VERSION 5.8 ;
BUSBITCHARS "[]" ;
DIVIDERCHAR "/" ;

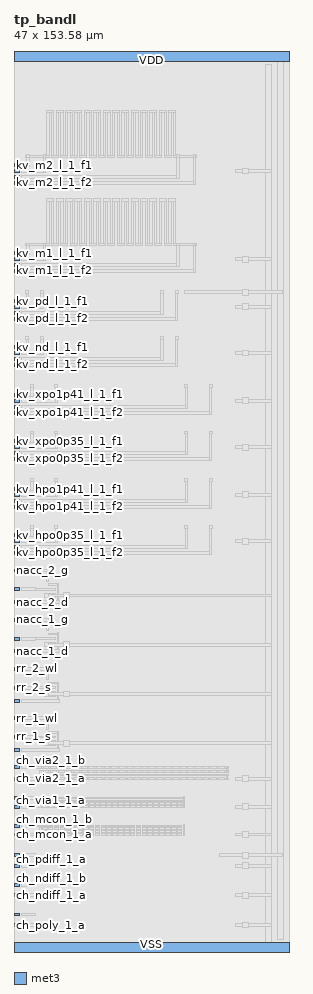
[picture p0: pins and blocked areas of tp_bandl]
MACRO tp_bandl
  CLASS BLOCK ;
  FOREIGN tp_bandl 0 0 ;
  ORIGIN 0 0 ;
  SIZE 47.000 BY 153.580 ;
  SYMMETRY X Y ;
  PIN VDD
    DIRECTION INOUT ;
    USE POWER ;
    PORT
      LAYER met3 ;
        RECT 0.000 151.980 47.000 153.580 ;
    END
  END VDD
  PIN VSS
    DIRECTION INOUT ;
    USE GROUND ;
    PORT
      LAYER met3 ;
        RECT 0.000 0.000 47.000 1.600 ;
    END
  END VSS
  PIN ch_mcon_1_a
    DIRECTION INOUT ;
    USE SIGNAL ;
    PORT
      LAYER met3 ;
        RECT 0.000 19.800 1.000 20.300 ;
    END
  END ch_mcon_1_a
  PIN ch_mcon_1_b
    DIRECTION INOUT ;
    USE SIGNAL ;
    PORT
      LAYER met3 ;
        RECT 0.000 21.300 1.000 21.800 ;
    END
  END ch_mcon_1_b
  PIN ch_ndiff_1_a
    DIRECTION INOUT ;
    USE SIGNAL ;
    PORT
      LAYER met3 ;
        RECT 0.000 9.400 1.000 9.900 ;
    END
  END ch_ndiff_1_a
  PIN ch_ndiff_1_b
    DIRECTION INOUT ;
    USE SIGNAL ;
    PORT
      LAYER met3 ;
        RECT 0.000 11.200 1.000 11.700 ;
    END
  END ch_ndiff_1_b
  PIN ch_pdiff_1_a
    DIRECTION INOUT ;
    USE SIGNAL ;
    PORT
      LAYER met3 ;
        RECT 0.000 14.450 1.000 14.950 ;
    END
  END ch_pdiff_1_a
  PIN ch_pdiff_1_b
    DIRECTION INOUT ;
    USE SIGNAL ;
    PORT
      LAYER met3 ;
        RECT 0.000 16.250 1.000 16.750 ;
    END
  END ch_pdiff_1_b
  PIN ch_poly_1_a
    DIRECTION INOUT ;
    USE SIGNAL ;
    PORT
      LAYER met3 ;
        RECT 0.000 4.350 1.000 4.850 ;
    END
  END ch_poly_1_a
  PIN ch_poly_1_b
    DIRECTION INOUT ;
    USE SIGNAL ;
    PORT
      LAYER met3 ;
        RECT 0.000 6.150 1.000 6.650 ;
    END
  END ch_poly_1_b
  PIN ch_via1_1_a
    DIRECTION INOUT ;
    USE SIGNAL ;
    PORT
      LAYER met3 ;
        RECT 0.000 24.550 1.000 25.050 ;
    END
  END ch_via1_1_a
  PIN ch_via1_1_b
    DIRECTION INOUT ;
    USE SIGNAL ;
    PORT
      LAYER met3 ;
        RECT 0.000 26.050 1.000 26.550 ;
    END
  END ch_via1_1_b
  PIN ch_via2_1_a
    DIRECTION INOUT ;
    USE SIGNAL ;
    PORT
      LAYER met3 ;
        RECT 0.000 29.300 1.000 29.800 ;
    END
  END ch_via2_1_a
  PIN ch_via2_1_b
    DIRECTION INOUT ;
    USE SIGNAL ;
    PORT
      LAYER met3 ;
        RECT 0.000 31.250 1.000 31.750 ;
    END
  END ch_via2_1_b
  PIN kv_hpo0p35_l_1_f1
    DIRECTION INOUT ;
    USE SIGNAL ;
    PORT
      LAYER met3 ;
        RECT 0.000 70.850 1.000 71.350 ;
    END
  END kv_hpo0p35_l_1_f1
  PIN kv_hpo0p35_l_1_f2
    DIRECTION INOUT ;
    USE SIGNAL ;
    PORT
      LAYER met3 ;
        RECT 0.000 67.850 1.000 68.350 ;
    END
  END kv_hpo0p35_l_1_f2
  PIN kv_hpo0p35_l_1_s1
    DIRECTION INOUT ;
    USE SIGNAL ;
    PORT
      LAYER met3 ;
        RECT 0.000 69.850 1.000 70.350 ;
    END
  END kv_hpo0p35_l_1_s1
  PIN kv_hpo0p35_l_1_s2
    DIRECTION INOUT ;
    USE SIGNAL ;
    PORT
      LAYER met3 ;
        RECT 0.000 68.850 1.000 69.350 ;
    END
  END kv_hpo0p35_l_1_s2
  PIN kv_hpo1p41_l_1_f1
    DIRECTION INOUT ;
    USE SIGNAL ;
    PORT
      LAYER met3 ;
        RECT 0.000 78.750 1.000 79.250 ;
    END
  END kv_hpo1p41_l_1_f1
  PIN kv_hpo1p41_l_1_f2
    DIRECTION INOUT ;
    USE SIGNAL ;
    PORT
      LAYER met3 ;
        RECT 0.000 75.750 1.000 76.250 ;
    END
  END kv_hpo1p41_l_1_f2
  PIN kv_hpo1p41_l_1_s1
    DIRECTION INOUT ;
    USE SIGNAL ;
    PORT
      LAYER met3 ;
        RECT 0.000 77.750 1.000 78.250 ;
    END
  END kv_hpo1p41_l_1_s1
  PIN kv_hpo1p41_l_1_s2
    DIRECTION INOUT ;
    USE SIGNAL ;
    PORT
      LAYER met3 ;
        RECT 0.000 76.750 1.000 77.250 ;
    END
  END kv_hpo1p41_l_1_s2
  PIN kv_m1_l_1_f1
    DIRECTION INOUT ;
    USE SIGNAL ;
    PORT
      LAYER met3 ;
        RECT 0.000 118.985 1.000 119.485 ;
    END
  END kv_m1_l_1_f1
  PIN kv_m1_l_1_f2
    DIRECTION INOUT ;
    USE SIGNAL ;
    PORT
      LAYER met3 ;
        RECT 0.000 115.985 1.000 116.485 ;
    END
  END kv_m1_l_1_f2
  PIN kv_m1_l_1_s1
    DIRECTION INOUT ;
    USE SIGNAL ;
    PORT
      LAYER met3 ;
        RECT 0.000 117.985 1.000 118.485 ;
    END
  END kv_m1_l_1_s1
  PIN kv_m1_l_1_s2
    DIRECTION INOUT ;
    USE SIGNAL ;
    PORT
      LAYER met3 ;
        RECT 0.000 116.985 1.000 117.485 ;
    END
  END kv_m1_l_1_s2
  PIN kv_m2_l_1_f1
    DIRECTION INOUT ;
    USE SIGNAL ;
    PORT
      LAYER met3 ;
        RECT 0.000 134.035 1.000 134.535 ;
    END
  END kv_m2_l_1_f1
  PIN kv_m2_l_1_f2
    DIRECTION INOUT ;
    USE SIGNAL ;
    PORT
      LAYER met3 ;
        RECT 0.000 131.035 1.000 131.535 ;
    END
  END kv_m2_l_1_f2
  PIN kv_m2_l_1_s1
    DIRECTION INOUT ;
    USE SIGNAL ;
    PORT
      LAYER met3 ;
        RECT 0.000 133.035 1.000 133.535 ;
    END
  END kv_m2_l_1_s1
  PIN kv_m2_l_1_s2
    DIRECTION INOUT ;
    USE SIGNAL ;
    PORT
      LAYER met3 ;
        RECT 0.000 132.035 1.000 132.535 ;
    END
  END kv_m2_l_1_s2
  PIN kv_nd_l_1_f1
    DIRECTION INOUT ;
    USE SIGNAL ;
    PORT
      LAYER met3 ;
        RECT 0.000 102.960 1.000 103.460 ;
    END
  END kv_nd_l_1_f1
  PIN kv_nd_l_1_f2
    DIRECTION INOUT ;
    USE SIGNAL ;
    PORT
      LAYER met3 ;
        RECT 0.000 99.960 1.000 100.460 ;
    END
  END kv_nd_l_1_f2
  PIN kv_nd_l_1_s1
    DIRECTION INOUT ;
    USE SIGNAL ;
    PORT
      LAYER met3 ;
        RECT 0.000 101.960 1.000 102.460 ;
    END
  END kv_nd_l_1_s1
  PIN kv_nd_l_1_s2
    DIRECTION INOUT ;
    USE SIGNAL ;
    PORT
      LAYER met3 ;
        RECT 0.000 100.960 1.000 101.460 ;
    END
  END kv_nd_l_1_s2
  PIN kv_pd_l_1_f1
    DIRECTION INOUT ;
    USE SIGNAL ;
    PORT
      LAYER met3 ;
        RECT 0.000 110.835 1.000 111.335 ;
    END
  END kv_pd_l_1_f1
  PIN kv_pd_l_1_f2
    DIRECTION INOUT ;
    USE SIGNAL ;
    PORT
      LAYER met3 ;
        RECT 0.000 107.835 1.000 108.335 ;
    END
  END kv_pd_l_1_f2
  PIN kv_pd_l_1_s1
    DIRECTION INOUT ;
    USE SIGNAL ;
    PORT
      LAYER met3 ;
        RECT 0.000 109.835 1.000 110.335 ;
    END
  END kv_pd_l_1_s1
  PIN kv_pd_l_1_s2
    DIRECTION INOUT ;
    USE SIGNAL ;
    PORT
      LAYER met3 ;
        RECT 0.000 108.835 1.000 109.335 ;
    END
  END kv_pd_l_1_s2
  PIN kv_xpo0p35_l_1_f1
    DIRECTION INOUT ;
    USE SIGNAL ;
    PORT
      LAYER met3 ;
        RECT 0.000 86.905 1.000 87.405 ;
    END
  END kv_xpo0p35_l_1_f1
  PIN kv_xpo0p35_l_1_f2
    DIRECTION INOUT ;
    USE SIGNAL ;
    PORT
      LAYER met3 ;
        RECT 0.000 83.905 1.000 84.405 ;
    END
  END kv_xpo0p35_l_1_f2
  PIN kv_xpo0p35_l_1_s1
    DIRECTION INOUT ;
    USE SIGNAL ;
    PORT
      LAYER met3 ;
        RECT 0.000 85.905 1.000 86.405 ;
    END
  END kv_xpo0p35_l_1_s1
  PIN kv_xpo0p35_l_1_s2
    DIRECTION INOUT ;
    USE SIGNAL ;
    PORT
      LAYER met3 ;
        RECT 0.000 84.905 1.000 85.405 ;
    END
  END kv_xpo0p35_l_1_s2
  PIN kv_xpo1p41_l_1_f1
    DIRECTION INOUT ;
    USE SIGNAL ;
    PORT
      LAYER met3 ;
        RECT 0.000 94.805 1.000 95.305 ;
    END
  END kv_xpo1p41_l_1_f1
  PIN kv_xpo1p41_l_1_f2
    DIRECTION INOUT ;
    USE SIGNAL ;
    PORT
      LAYER met3 ;
        RECT 0.000 91.805 1.000 92.305 ;
    END
  END kv_xpo1p41_l_1_f2
  PIN kv_xpo1p41_l_1_s1
    DIRECTION INOUT ;
    USE SIGNAL ;
    PORT
      LAYER met3 ;
        RECT 0.000 93.805 1.000 94.305 ;
    END
  END kv_xpo1p41_l_1_s1
  PIN kv_xpo1p41_l_1_s2
    DIRECTION INOUT ;
    USE SIGNAL ;
    PORT
      LAYER met3 ;
        RECT 0.000 92.805 1.000 93.305 ;
    END
  END kv_xpo1p41_l_1_s2
  PIN nacc_1_d
    DIRECTION INOUT ;
    USE SIGNAL ;
    PORT
      LAYER met3 ;
        RECT 0.000 51.050 1.000 51.550 ;
    END
  END nacc_1_d
  PIN nacc_1_g
    DIRECTION INOUT ;
    USE SIGNAL ;
    PORT
      LAYER met3 ;
        RECT 0.000 56.450 1.000 56.950 ;
    END
  END nacc_1_g
  PIN nacc_1_s
    DIRECTION INOUT ;
    USE SIGNAL ;
    PORT
      LAYER met3 ;
        RECT 0.000 53.240 1.000 53.740 ;
    END
  END nacc_1_s
  PIN nacc_2_d
    DIRECTION INOUT ;
    USE SIGNAL ;
    PORT
      LAYER met3 ;
        RECT 0.000 59.450 1.000 59.950 ;
    END
  END nacc_2_d
  PIN nacc_2_g
    DIRECTION INOUT ;
    USE SIGNAL ;
    PORT
      LAYER met3 ;
        RECT 0.000 64.850 1.000 65.350 ;
    END
  END nacc_2_g
  PIN nacc_2_s
    DIRECTION INOUT ;
    USE SIGNAL ;
    PORT
      LAYER met3 ;
        RECT 0.000 61.640 1.000 62.140 ;
    END
  END nacc_2_s
  PIN rr_1_s
    DIRECTION INOUT ;
    USE SIGNAL ;
    PORT
      LAYER met3 ;
        RECT 0.000 36.440 1.000 36.940 ;
    END
  END rr_1_s
  PIN rr_1_te
    DIRECTION INOUT ;
    USE SIGNAL ;
    PORT
      LAYER met3 ;
        RECT 0.000 34.250 1.000 34.750 ;
    END
  END rr_1_te
  PIN rr_1_wl
    DIRECTION INOUT ;
    USE SIGNAL ;
    PORT
      LAYER met3 ;
        RECT 0.000 39.650 1.000 40.150 ;
    END
  END rr_1_wl
  PIN rr_2_s
    DIRECTION INOUT ;
    USE SIGNAL ;
    PORT
      LAYER met3 ;
        RECT 0.000 44.840 1.000 45.340 ;
    END
  END rr_2_s
  PIN rr_2_te
    DIRECTION INOUT ;
    USE SIGNAL ;
    PORT
      LAYER met3 ;
        RECT 0.000 42.650 1.000 43.150 ;
    END
  END rr_2_te
  PIN rr_2_wl
    DIRECTION INOUT ;
    USE SIGNAL ;
    PORT
      LAYER met3 ;
        RECT 0.000 48.050 1.000 48.550 ;
    END
  END rr_2_wl
  OBS
    LAYER li1 ;
      RECT 0.000 0.000 47.000 153.580 ;
    LAYER met1 ;
      RECT 19.855 19.935 20.645 20.165 ;
      RECT 19.855 20.435 20.645 20.665 ;
      RECT 19.855 20.935 20.645 21.165 ;
      RECT 19.855 21.435 20.645 21.665 ;
      RECT 19.340 24.670 20.160 24.930 ;
      RECT 19.340 25.170 20.160 25.430 ;
      RECT 19.340 25.670 20.160 25.930 ;
      RECT 19.340 26.170 20.160 26.430 ;
      RECT 5.600 120.935 6.000 128.135 ;
      RECT 2.000 120.535 6.000 120.935 ;
      RECT 7.200 120.935 7.600 128.135 ;
      RECT 6.400 120.535 7.600 120.935 ;
      RECT 8.800 120.935 9.200 128.135 ;
      RECT 8.000 120.535 9.200 120.935 ;
      RECT 10.400 120.935 10.800 128.135 ;
      RECT 9.600 120.535 10.800 120.935 ;
      RECT 12.000 120.935 12.400 128.135 ;
      RECT 11.200 120.535 12.400 120.935 ;
      RECT 13.600 120.935 14.000 128.135 ;
      RECT 12.800 120.535 14.000 120.935 ;
      RECT 15.200 120.935 15.600 128.135 ;
      RECT 14.400 120.535 15.600 120.935 ;
      RECT 16.800 120.935 17.200 128.135 ;
      RECT 16.000 120.535 17.200 120.935 ;
      RECT 18.400 120.935 18.800 128.135 ;
      RECT 17.600 120.535 18.800 120.935 ;
      RECT 20.000 120.935 20.400 128.135 ;
      RECT 19.200 120.535 20.400 120.935 ;
      RECT 21.600 120.935 22.000 128.135 ;
      RECT 20.800 120.535 22.000 120.935 ;
      RECT 23.200 120.935 23.600 128.135 ;
      RECT 22.400 120.535 23.600 120.935 ;
      RECT 24.800 120.935 25.200 128.135 ;
      RECT 24.000 120.535 25.200 120.935 ;
      RECT 26.400 120.935 26.800 128.135 ;
      RECT 25.600 120.535 26.800 120.935 ;
      RECT 5.600 128.135 6.800 128.535 ;
      RECT 6.400 120.935 6.800 128.135 ;
      RECT 7.200 128.135 8.400 128.535 ;
      RECT 8.000 120.935 8.400 128.135 ;
      RECT 8.800 128.135 10.000 128.535 ;
      RECT 9.600 120.935 10.000 128.135 ;
      RECT 10.400 128.135 11.600 128.535 ;
      RECT 11.200 120.935 11.600 128.135 ;
      RECT 12.000 128.135 13.200 128.535 ;
      RECT 12.800 120.935 13.200 128.135 ;
      RECT 13.600 128.135 14.800 128.535 ;
      RECT 14.400 120.935 14.800 128.135 ;
      RECT 15.200 128.135 16.400 128.535 ;
      RECT 16.000 120.935 16.400 128.135 ;
      RECT 16.800 128.135 18.000 128.535 ;
      RECT 17.600 120.935 18.000 128.135 ;
      RECT 18.400 128.135 19.600 128.535 ;
      RECT 19.200 120.935 19.600 128.135 ;
      RECT 20.000 128.135 21.200 128.535 ;
      RECT 20.800 120.935 21.200 128.135 ;
      RECT 21.600 128.135 22.800 128.535 ;
      RECT 22.400 120.935 22.800 128.135 ;
      RECT 23.200 128.135 24.400 128.535 ;
      RECT 24.000 120.935 24.400 128.135 ;
      RECT 24.800 128.135 26.000 128.535 ;
      RECT 25.600 120.935 26.000 128.135 ;
      RECT 27.200 120.535 31.200 120.935 ;
      RECT 26.400 128.135 27.600 128.535 ;
      RECT 27.200 120.935 27.600 128.135 ;
      RECT 29.240 72.440 29.560 72.760 ;
      RECT 33.400 72.440 33.720 72.760 ;
      RECT 37.840 77.840 38.160 78.160 ;
      RECT 29.240 80.340 29.560 80.660 ;
      RECT 33.400 80.340 33.720 80.660 ;
      RECT 37.840 85.995 38.160 86.315 ;
      RECT 29.240 88.495 29.560 88.815 ;
      RECT 33.400 88.495 33.720 88.815 ;
      RECT 37.840 93.895 38.160 94.215 ;
      RECT 29.240 96.395 29.560 96.715 ;
      RECT 33.400 96.395 33.720 96.715 ;
      RECT 37.840 102.050 38.160 102.370 ;
      RECT 25.090 104.550 25.410 104.870 ;
      RECT 27.590 104.550 27.910 104.870 ;
      RECT 37.840 109.925 38.160 110.245 ;
      RECT 25.090 112.425 25.410 112.745 ;
      RECT 27.590 112.425 27.910 112.745 ;
      RECT 29.140 112.425 29.460 112.745 ;
      RECT 37.840 118.075 38.160 118.395 ;
      RECT 37.840 69.940 38.160 70.260 ;
      RECT 37.840 133.125 38.160 133.445 ;
      RECT 4.590 104.550 4.910 104.870 ;
      RECT 7.080 80.340 7.400 80.660 ;
      RECT 7.080 72.440 7.400 72.760 ;
      RECT 2.920 72.440 3.240 72.760 ;
      RECT 2.090 112.425 2.410 112.745 ;
      RECT 4.590 112.425 4.910 112.745 ;
      RECT 2.920 96.395 3.240 96.715 ;
      RECT 7.080 96.395 7.400 96.715 ;
      RECT 2.920 80.340 3.240 80.660 ;
      RECT 2.920 88.495 3.240 88.815 ;
      RECT 7.080 88.495 7.400 88.815 ;
      RECT 2.090 104.550 2.410 104.870 ;
      RECT 10.855 20.935 11.645 21.165 ;
      RECT 10.855 21.435 11.645 21.665 ;
      RECT 10.340 24.670 11.160 24.930 ;
      RECT 10.340 25.170 11.160 25.430 ;
      RECT 10.340 25.670 11.160 25.930 ;
      RECT 10.340 26.170 11.160 26.430 ;
      RECT 3.200 36.545 3.290 36.835 ;
      RECT 3.610 36.545 7.020 36.835 ;
      RECT 3.290 36.530 3.610 36.850 ;
      RECT 10.855 19.935 11.645 20.165 ;
      RECT 10.855 20.435 11.645 20.665 ;
      RECT 5.180 43.660 7.000 44.410 ;
      RECT 3.200 44.945 3.290 45.235 ;
      RECT 3.610 44.945 7.020 45.235 ;
      RECT 3.290 44.930 3.610 45.250 ;
      RECT 5.945 45.745 7.665 46.035 ;
      RECT 5.530 46.460 5.850 46.780 ;
      RECT 5.180 52.060 7.000 52.810 ;
      RECT 3.200 53.345 3.290 53.635 ;
      RECT 3.610 53.345 7.020 53.635 ;
      RECT 3.290 53.330 3.610 53.650 ;
      RECT 5.945 54.145 7.665 54.435 ;
      RECT 5.530 54.860 5.850 55.180 ;
      RECT 5.180 60.460 7.000 61.210 ;
      RECT 3.200 61.745 3.290 62.035 ;
      RECT 3.610 61.745 7.020 62.035 ;
      RECT 3.290 61.730 3.610 62.050 ;
      RECT 5.945 62.545 7.665 62.835 ;
      RECT 5.530 63.260 5.850 63.580 ;
      RECT 5.945 37.345 7.665 37.635 ;
      RECT 5.530 38.060 5.850 38.380 ;
      RECT 4.340 25.170 5.160 25.430 ;
      RECT 5.340 25.170 6.160 25.430 ;
      RECT 6.340 25.170 7.160 25.430 ;
      RECT 7.340 25.170 8.160 25.430 ;
      RECT 8.340 25.170 9.160 25.430 ;
      RECT 9.340 25.170 10.160 25.430 ;
      RECT 7.855 20.935 8.645 21.165 ;
      RECT 3.340 16.340 3.660 16.660 ;
      RECT 4.340 25.670 5.160 25.930 ;
      RECT 5.340 25.670 6.160 25.930 ;
      RECT 6.340 25.670 7.160 25.930 ;
      RECT 7.340 25.670 8.160 25.930 ;
      RECT 8.340 25.670 9.160 25.930 ;
      RECT 9.340 25.670 10.160 25.930 ;
      RECT 3.340 9.490 3.660 9.810 ;
      RECT 4.855 19.935 5.645 20.165 ;
      RECT 4.340 26.170 5.160 26.430 ;
      RECT 5.340 26.170 6.160 26.430 ;
      RECT 6.340 26.170 7.160 26.430 ;
      RECT 7.340 26.170 8.160 26.430 ;
      RECT 8.340 26.170 9.160 26.430 ;
      RECT 9.340 26.170 10.160 26.430 ;
      RECT 4.385 20.405 4.615 21.195 ;
      RECT 5.855 19.935 6.645 20.165 ;
      RECT 5.180 35.260 7.000 36.010 ;
      RECT 4.855 21.435 5.645 21.665 ;
      RECT 5.855 21.435 6.645 21.665 ;
      RECT 6.855 21.435 7.645 21.665 ;
      RECT 7.855 21.435 8.645 21.665 ;
      RECT 8.855 21.435 9.645 21.665 ;
      RECT 9.855 21.435 10.645 21.665 ;
      RECT 8.855 20.935 9.645 21.165 ;
      RECT 3.340 11.290 3.660 11.610 ;
      RECT 3.660 21.435 4.645 21.665 ;
      RECT 3.340 21.390 3.660 21.710 ;
      RECT 4.340 24.670 5.160 24.930 ;
      RECT 5.340 24.670 6.160 24.930 ;
      RECT 6.340 24.670 7.160 24.930 ;
      RECT 7.340 24.670 8.160 24.930 ;
      RECT 8.340 24.670 9.160 24.930 ;
      RECT 9.340 24.670 10.160 24.930 ;
      RECT 6.855 19.935 7.645 20.165 ;
      RECT 7.855 19.935 8.645 20.165 ;
      RECT 8.855 19.935 9.645 20.165 ;
      RECT 9.855 19.935 10.645 20.165 ;
      RECT 9.855 20.935 10.645 21.165 ;
      RECT 3.340 4.440 3.660 4.760 ;
      RECT 3.660 19.935 4.645 20.165 ;
      RECT 3.340 19.890 3.660 20.210 ;
      RECT 4.855 20.435 5.645 20.665 ;
      RECT 5.855 20.435 6.645 20.665 ;
      RECT 6.855 20.435 7.645 20.665 ;
      RECT 7.855 20.435 8.645 20.665 ;
      RECT 8.855 20.435 9.645 20.665 ;
      RECT 9.855 20.435 10.645 20.665 ;
      RECT 3.340 14.540 3.660 14.860 ;
      RECT 3.340 6.240 3.660 6.560 ;
      RECT 4.855 20.935 5.645 21.165 ;
      RECT 5.855 20.935 6.645 21.165 ;
      RECT 6.855 20.935 7.645 21.165 ;
      RECT 14.340 24.670 15.160 24.930 ;
      RECT 15.340 24.670 16.160 24.930 ;
      RECT 16.340 24.670 17.160 24.930 ;
      RECT 17.340 24.670 18.160 24.930 ;
      RECT 18.340 24.670 19.160 24.930 ;
      RECT 11.340 26.170 12.160 26.430 ;
      RECT 12.340 26.170 13.160 26.430 ;
      RECT 13.340 26.170 14.160 26.430 ;
      RECT 14.340 26.170 15.160 26.430 ;
      RECT 15.340 26.170 16.160 26.430 ;
      RECT 16.340 26.170 17.160 26.430 ;
      RECT 17.340 26.170 18.160 26.430 ;
      RECT 18.340 26.170 19.160 26.430 ;
      RECT 12.855 21.435 13.645 21.665 ;
      RECT 13.855 21.435 14.645 21.665 ;
      RECT 14.855 21.435 15.645 21.665 ;
      RECT 15.855 21.435 16.645 21.665 ;
      RECT 16.855 21.435 17.645 21.665 ;
      RECT 17.855 21.435 18.645 21.665 ;
      RECT 18.855 21.435 19.645 21.665 ;
      RECT 12.855 20.935 13.645 21.165 ;
      RECT 11.340 25.170 12.160 25.430 ;
      RECT 12.340 25.170 13.160 25.430 ;
      RECT 13.340 25.170 14.160 25.430 ;
      RECT 14.340 25.170 15.160 25.430 ;
      RECT 15.340 25.170 16.160 25.430 ;
      RECT 16.340 25.170 17.160 25.430 ;
      RECT 17.340 25.170 18.160 25.430 ;
      RECT 18.340 25.170 19.160 25.430 ;
      RECT 13.855 20.935 14.645 21.165 ;
      RECT 14.855 20.935 15.645 21.165 ;
      RECT 15.855 20.935 16.645 21.165 ;
      RECT 16.855 20.935 17.645 21.165 ;
      RECT 17.855 20.935 18.645 21.165 ;
      RECT 18.855 20.935 19.645 21.165 ;
      RECT 11.855 19.935 12.645 20.165 ;
      RECT 12.855 19.935 13.645 20.165 ;
      RECT 13.855 19.935 14.645 20.165 ;
      RECT 14.855 19.935 15.645 20.165 ;
      RECT 15.855 19.935 16.645 20.165 ;
      RECT 16.855 19.935 17.645 20.165 ;
      RECT 17.855 19.935 18.645 20.165 ;
      RECT 18.855 19.935 19.645 20.165 ;
      RECT 11.855 20.935 12.645 21.165 ;
      RECT 11.855 21.435 12.645 21.665 ;
      RECT 11.340 25.670 12.160 25.930 ;
      RECT 12.340 25.670 13.160 25.930 ;
      RECT 13.340 25.670 14.160 25.930 ;
      RECT 14.340 25.670 15.160 25.930 ;
      RECT 15.340 25.670 16.160 25.930 ;
      RECT 16.340 25.670 17.160 25.930 ;
      RECT 17.340 25.670 18.160 25.930 ;
      RECT 11.855 20.435 12.645 20.665 ;
      RECT 12.855 20.435 13.645 20.665 ;
      RECT 13.855 20.435 14.645 20.665 ;
      RECT 14.855 20.435 15.645 20.665 ;
      RECT 15.855 20.435 16.645 20.665 ;
      RECT 16.855 20.435 17.645 20.665 ;
      RECT 17.855 20.435 18.645 20.665 ;
      RECT 18.855 20.435 19.645 20.665 ;
      RECT 18.340 25.670 19.160 25.930 ;
      RECT 11.340 24.670 12.160 24.930 ;
      RECT 12.340 24.670 13.160 24.930 ;
      RECT 13.340 24.670 14.160 24.930 ;
      RECT 28.340 25.670 29.160 25.930 ;
      RECT 25.855 20.935 26.645 21.165 ;
      RECT 26.855 20.935 27.645 21.165 ;
      RECT 27.855 20.935 28.645 21.165 ;
      RECT 23.855 20.435 24.645 20.665 ;
      RECT 24.855 20.435 25.645 20.665 ;
      RECT 25.855 20.435 26.645 20.665 ;
      RECT 26.855 20.435 27.645 20.665 ;
      RECT 20.340 24.670 21.160 24.930 ;
      RECT 21.340 24.670 22.160 24.930 ;
      RECT 22.340 24.670 23.160 24.930 ;
      RECT 23.340 24.670 24.160 24.930 ;
      RECT 24.340 24.670 25.160 24.930 ;
      RECT 25.340 24.670 26.160 24.930 ;
      RECT 26.340 24.670 27.160 24.930 ;
      RECT 27.340 24.670 28.160 24.930 ;
      RECT 28.340 24.670 29.160 24.930 ;
      RECT 20.340 26.170 21.160 26.430 ;
      RECT 21.340 26.170 22.160 26.430 ;
      RECT 22.340 26.170 23.160 26.430 ;
      RECT 23.340 26.170 24.160 26.430 ;
      RECT 24.340 26.170 25.160 26.430 ;
      RECT 25.340 26.170 26.160 26.430 ;
      RECT 26.340 26.170 27.160 26.430 ;
      RECT 27.340 26.170 28.160 26.430 ;
      RECT 28.340 26.170 29.160 26.430 ;
      RECT 37.840 29.390 38.160 29.710 ;
      RECT 37.840 24.640 38.160 24.960 ;
      RECT 27.855 20.435 28.645 20.665 ;
      RECT 28.885 19.905 29.115 20.695 ;
      RECT 20.855 19.935 21.645 20.165 ;
      RECT 21.855 19.935 22.645 20.165 ;
      RECT 22.855 19.935 23.645 20.165 ;
      RECT 23.855 19.935 24.645 20.165 ;
      RECT 24.855 19.935 25.645 20.165 ;
      RECT 25.855 19.935 26.645 20.165 ;
      RECT 26.855 19.935 27.645 20.165 ;
      RECT 27.855 19.935 28.645 20.165 ;
      RECT 37.840 9.490 38.160 9.810 ;
      RECT 37.840 19.890 38.160 20.210 ;
      RECT 37.840 14.540 38.160 14.860 ;
      RECT 20.855 21.435 21.645 21.665 ;
      RECT 21.855 21.435 22.645 21.665 ;
      RECT 22.855 21.435 23.645 21.665 ;
      RECT 20.340 25.170 21.160 25.430 ;
      RECT 21.340 25.170 22.160 25.430 ;
      RECT 22.340 25.170 23.160 25.430 ;
      RECT 23.340 25.170 24.160 25.430 ;
      RECT 24.340 25.170 25.160 25.430 ;
      RECT 25.340 25.170 26.160 25.430 ;
      RECT 26.340 25.170 27.160 25.430 ;
      RECT 27.340 25.170 28.160 25.430 ;
      RECT 28.340 25.170 29.160 25.430 ;
      RECT 23.855 21.435 24.645 21.665 ;
      RECT 24.855 21.435 25.645 21.665 ;
      RECT 25.855 21.435 26.645 21.665 ;
      RECT 26.855 21.435 27.645 21.665 ;
      RECT 27.855 21.435 28.645 21.665 ;
      RECT 28.885 20.905 29.115 21.695 ;
      RECT 37.840 4.440 38.160 4.760 ;
      RECT 35.240 16.340 35.560 16.660 ;
      RECT 20.855 20.435 21.645 20.665 ;
      RECT 21.855 20.435 22.645 20.665 ;
      RECT 22.855 20.435 23.645 20.665 ;
      RECT 20.855 20.935 21.645 21.165 ;
      RECT 21.855 20.935 22.645 21.165 ;
      RECT 22.855 20.935 23.645 21.165 ;
      RECT 23.855 20.935 24.645 21.165 ;
      RECT 24.855 20.935 25.645 21.165 ;
      RECT 20.340 25.670 21.160 25.930 ;
      RECT 21.340 25.670 22.160 25.930 ;
      RECT 22.340 25.670 23.160 25.930 ;
      RECT 23.340 25.670 24.160 25.930 ;
      RECT 24.340 25.670 25.160 25.930 ;
      RECT 25.340 25.670 26.160 25.930 ;
      RECT 26.340 25.670 27.160 25.930 ;
      RECT 27.340 25.670 28.160 25.930 ;
    LAYER met2 ;
      RECT 23.840 24.670 24.660 24.930 ;
      RECT 23.840 25.170 24.660 25.430 ;
      RECT 23.840 25.670 24.660 25.930 ;
      RECT 23.840 26.170 24.660 26.430 ;
      RECT 23.815 29.410 24.835 29.690 ;
      RECT 23.815 30.060 24.835 30.340 ;
      RECT 23.815 30.710 24.835 30.990 ;
      RECT 23.815 31.360 24.835 31.640 ;
      RECT 5.600 135.985 6.000 143.185 ;
      RECT 2.000 135.585 6.000 135.985 ;
      RECT 7.200 135.985 7.600 143.185 ;
      RECT 6.400 135.585 7.600 135.985 ;
      RECT 8.800 135.985 9.200 143.185 ;
      RECT 8.000 135.585 9.200 135.985 ;
      RECT 10.400 135.985 10.800 143.185 ;
      RECT 9.600 135.585 10.800 135.985 ;
      RECT 12.000 135.985 12.400 143.185 ;
      RECT 11.200 135.585 12.400 135.985 ;
      RECT 13.600 135.985 14.000 143.185 ;
      RECT 12.800 135.585 14.000 135.985 ;
      RECT 15.200 135.985 15.600 143.185 ;
      RECT 14.400 135.585 15.600 135.985 ;
      RECT 16.800 135.985 17.200 143.185 ;
      RECT 16.000 135.585 17.200 135.985 ;
      RECT 18.400 135.985 18.800 143.185 ;
      RECT 17.600 135.585 18.800 135.985 ;
      RECT 20.000 135.985 20.400 143.185 ;
      RECT 19.200 135.585 20.400 135.985 ;
      RECT 21.600 135.985 22.000 143.185 ;
      RECT 20.800 135.585 22.000 135.985 ;
      RECT 23.200 135.985 23.600 143.185 ;
      RECT 22.400 135.585 23.600 135.985 ;
      RECT 24.800 135.985 25.200 143.185 ;
      RECT 24.000 135.585 25.200 135.985 ;
      RECT 26.400 135.985 26.800 143.185 ;
      RECT 25.600 135.585 26.800 135.985 ;
      RECT 5.600 143.185 6.800 143.585 ;
      RECT 6.400 135.985 6.800 143.185 ;
      RECT 7.200 143.185 8.400 143.585 ;
      RECT 8.000 135.985 8.400 143.185 ;
      RECT 8.800 143.185 10.000 143.585 ;
      RECT 9.600 135.985 10.000 143.185 ;
      RECT 10.400 143.185 11.600 143.585 ;
      RECT 11.200 135.985 11.600 143.185 ;
      RECT 12.000 143.185 13.200 143.585 ;
      RECT 12.800 135.985 13.200 143.185 ;
      RECT 13.600 143.185 14.800 143.585 ;
      RECT 14.400 135.985 14.800 143.185 ;
      RECT 15.200 143.185 16.400 143.585 ;
      RECT 16.000 135.985 16.400 143.185 ;
      RECT 16.800 143.185 18.000 143.585 ;
      RECT 17.600 135.985 18.000 143.185 ;
      RECT 18.400 143.185 19.600 143.585 ;
      RECT 19.200 135.985 19.600 143.185 ;
      RECT 20.000 143.185 21.200 143.585 ;
      RECT 20.800 135.985 21.200 143.185 ;
      RECT 21.600 143.185 22.800 143.585 ;
      RECT 22.400 135.985 22.800 143.185 ;
      RECT 23.200 143.185 24.400 143.585 ;
      RECT 24.000 135.985 24.400 143.185 ;
      RECT 24.800 143.185 26.000 143.585 ;
      RECT 25.600 135.985 26.000 143.185 ;
      RECT 27.200 135.585 31.200 135.985 ;
      RECT 26.400 143.185 27.600 143.585 ;
      RECT 27.200 135.985 27.600 143.185 ;
      RECT 43.000 0.200 44.000 151.380 ;
      RECT 45.000 2.200 46.000 153.380 ;
      RECT 37.815 85.970 38.185 86.340 ;
      RECT 29.215 88.470 29.585 88.840 ;
      RECT 33.375 88.470 33.745 88.840 ;
      RECT 37.815 93.870 38.185 94.240 ;
      RECT 29.215 96.370 29.585 96.740 ;
      RECT 33.375 96.370 33.745 96.740 ;
      RECT 37.815 102.025 38.185 102.395 ;
      RECT 25.065 104.525 25.435 104.895 ;
      RECT 27.565 104.525 27.935 104.895 ;
      RECT 37.815 109.900 38.185 110.270 ;
      RECT 25.065 112.400 25.435 112.770 ;
      RECT 27.565 112.400 27.935 112.770 ;
      RECT 29.115 112.400 29.485 112.770 ;
      RECT 37.815 118.050 38.185 118.420 ;
      RECT 27.815 120.550 28.185 120.920 ;
      RECT 30.615 120.550 30.985 120.920 ;
      RECT 37.815 133.100 38.185 133.470 ;
      RECT 37.815 77.815 38.185 78.185 ;
      RECT 29.215 80.315 29.585 80.685 ;
      RECT 33.375 80.315 33.745 80.685 ;
      RECT 7.055 88.470 7.425 88.840 ;
      RECT 7.055 80.315 7.425 80.685 ;
      RECT 2.895 80.315 3.265 80.685 ;
      RECT 2.065 104.525 2.435 104.895 ;
      RECT 2.215 120.550 2.585 120.920 ;
      RECT 5.015 120.550 5.385 120.920 ;
      RECT 4.565 104.525 4.935 104.895 ;
      RECT 2.895 88.470 3.265 88.840 ;
      RECT 2.895 96.370 3.265 96.740 ;
      RECT 7.055 96.370 7.425 96.740 ;
      RECT 2.065 112.400 2.435 112.770 ;
      RECT 4.565 112.400 4.935 112.770 ;
      RECT 12.840 25.670 13.660 25.930 ;
      RECT 12.840 26.170 13.660 26.430 ;
      RECT 12.115 29.410 13.135 29.690 ;
      RECT 12.115 30.060 13.135 30.340 ;
      RECT 12.115 30.710 13.135 30.990 ;
      RECT 12.115 31.360 13.135 31.640 ;
      RECT 5.505 38.020 5.875 40.085 ;
      RECT 12.840 24.670 13.660 24.930 ;
      RECT 12.840 25.170 13.660 25.430 ;
      RECT 7.375 45.900 7.635 46.050 ;
      RECT 7.345 43.085 7.665 45.900 ;
      RECT 7.320 42.715 7.690 43.085 ;
      RECT 5.505 46.420 5.875 48.485 ;
      RECT 6.015 52.250 6.385 52.620 ;
      RECT 3.265 53.305 3.635 53.675 ;
      RECT 7.375 54.300 7.635 54.450 ;
      RECT 7.345 51.485 7.665 54.300 ;
      RECT 7.320 51.115 7.690 51.485 ;
      RECT 5.505 54.820 5.875 56.885 ;
      RECT 6.015 60.650 6.385 61.020 ;
      RECT 3.265 61.705 3.635 62.075 ;
      RECT 7.375 62.700 7.635 62.850 ;
      RECT 7.345 59.885 7.665 62.700 ;
      RECT 7.320 59.515 7.690 59.885 ;
      RECT 5.505 63.220 5.875 65.285 ;
      RECT 2.895 72.415 3.265 72.785 ;
      RECT 7.055 72.415 7.425 72.785 ;
      RECT 6.015 43.850 6.385 44.220 ;
      RECT 3.265 44.905 3.635 45.275 ;
      RECT 4.315 29.410 5.335 29.690 ;
      RECT 5.615 29.410 6.635 29.690 ;
      RECT 6.915 29.410 7.935 29.690 ;
      RECT 8.215 29.410 9.235 29.690 ;
      RECT 9.515 29.410 10.535 29.690 ;
      RECT 10.815 29.410 11.835 29.690 ;
      RECT 5.840 25.670 6.660 25.930 ;
      RECT 3.315 14.515 3.685 14.885 ;
      RECT 4.315 30.060 5.335 30.340 ;
      RECT 5.615 30.060 6.635 30.340 ;
      RECT 6.915 30.060 7.935 30.340 ;
      RECT 8.215 30.060 9.235 30.340 ;
      RECT 9.515 30.060 10.535 30.340 ;
      RECT 10.815 30.060 11.835 30.340 ;
      RECT 6.840 25.670 7.660 25.930 ;
      RECT 3.315 16.315 3.685 16.685 ;
      RECT 4.315 30.710 5.335 30.990 ;
      RECT 5.615 30.710 6.635 30.990 ;
      RECT 6.915 30.710 7.935 30.990 ;
      RECT 8.215 30.710 9.235 30.990 ;
      RECT 9.515 30.710 10.535 30.990 ;
      RECT 10.815 30.710 11.835 30.990 ;
      RECT 7.840 25.670 8.660 25.930 ;
      RECT 3.315 19.865 3.685 20.235 ;
      RECT 4.315 31.360 5.335 31.640 ;
      RECT 5.615 31.360 6.635 31.640 ;
      RECT 6.915 31.360 7.935 31.640 ;
      RECT 8.215 31.360 9.235 31.640 ;
      RECT 9.515 31.360 10.535 31.640 ;
      RECT 10.815 31.360 11.835 31.640 ;
      RECT 8.840 25.670 9.660 25.930 ;
      RECT 3.315 21.365 3.685 21.735 ;
      RECT 6.015 35.450 6.385 35.820 ;
      RECT 3.265 36.505 3.635 36.875 ;
      RECT 7.375 37.500 7.635 37.650 ;
      RECT 7.345 34.685 7.665 37.500 ;
      RECT 7.320 34.315 7.690 34.685 ;
      RECT 9.840 25.670 10.660 25.930 ;
      RECT 10.840 25.670 11.660 25.930 ;
      RECT 11.840 25.670 12.660 25.930 ;
      RECT 3.315 6.215 3.685 6.585 ;
      RECT 3.315 9.465 3.685 9.835 ;
      RECT 4.370 25.140 4.630 25.960 ;
      RECT 4.840 26.170 5.660 26.430 ;
      RECT 5.840 26.170 6.660 26.430 ;
      RECT 6.840 26.170 7.660 26.430 ;
      RECT 7.840 26.170 8.660 26.430 ;
      RECT 8.840 26.170 9.660 26.430 ;
      RECT 9.840 26.170 10.660 26.430 ;
      RECT 10.840 26.170 11.660 26.430 ;
      RECT 11.840 26.170 12.660 26.430 ;
      RECT 4.840 25.670 5.660 25.930 ;
      RECT 4.840 24.670 5.660 24.930 ;
      RECT 5.840 24.670 6.660 24.930 ;
      RECT 6.840 24.670 7.660 24.930 ;
      RECT 7.840 24.670 8.660 24.930 ;
      RECT 8.840 24.670 9.660 24.930 ;
      RECT 9.840 24.670 10.660 24.930 ;
      RECT 10.840 24.670 11.660 24.930 ;
      RECT 11.840 24.670 12.660 24.930 ;
      RECT 3.315 11.265 3.685 11.635 ;
      RECT 3.315 4.415 3.685 4.785 ;
      RECT 3.685 24.670 4.660 24.930 ;
      RECT 3.315 24.615 3.685 24.985 ;
      RECT 4.840 25.170 5.660 25.430 ;
      RECT 5.840 25.170 6.660 25.430 ;
      RECT 6.840 25.170 7.660 25.430 ;
      RECT 7.840 25.170 8.660 25.430 ;
      RECT 8.840 25.170 9.660 25.430 ;
      RECT 9.840 25.170 10.660 25.430 ;
      RECT 10.840 25.170 11.660 25.430 ;
      RECT 11.840 25.170 12.660 25.430 ;
      RECT 3.685 26.170 4.660 26.430 ;
      RECT 3.315 26.115 3.685 26.485 ;
      RECT 21.215 30.710 22.235 30.990 ;
      RECT 22.515 30.710 23.535 30.990 ;
      RECT 19.840 25.670 20.660 25.930 ;
      RECT 20.840 25.670 21.660 25.930 ;
      RECT 21.840 25.670 22.660 25.930 ;
      RECT 22.840 25.670 23.660 25.930 ;
      RECT 18.840 25.170 19.660 25.430 ;
      RECT 19.840 25.170 20.660 25.430 ;
      RECT 20.840 25.170 21.660 25.430 ;
      RECT 21.840 25.170 22.660 25.430 ;
      RECT 13.415 31.360 14.435 31.640 ;
      RECT 14.715 31.360 15.735 31.640 ;
      RECT 16.015 31.360 17.035 31.640 ;
      RECT 17.315 31.360 18.335 31.640 ;
      RECT 18.615 31.360 19.635 31.640 ;
      RECT 19.915 31.360 20.935 31.640 ;
      RECT 21.215 31.360 22.235 31.640 ;
      RECT 22.515 31.360 23.535 31.640 ;
      RECT 22.840 25.170 23.660 25.430 ;
      RECT 13.415 29.410 14.435 29.690 ;
      RECT 14.715 29.410 15.735 29.690 ;
      RECT 16.015 29.410 17.035 29.690 ;
      RECT 17.315 29.410 18.335 29.690 ;
      RECT 18.615 29.410 19.635 29.690 ;
      RECT 19.915 29.410 20.935 29.690 ;
      RECT 21.215 29.410 22.235 29.690 ;
      RECT 22.515 29.410 23.535 29.690 ;
      RECT 13.840 25.670 14.660 25.930 ;
      RECT 14.840 25.670 15.660 25.930 ;
      RECT 15.840 25.670 16.660 25.930 ;
      RECT 16.840 25.670 17.660 25.930 ;
      RECT 17.840 25.670 18.660 25.930 ;
      RECT 18.840 25.670 19.660 25.930 ;
      RECT 13.840 26.170 14.660 26.430 ;
      RECT 14.840 26.170 15.660 26.430 ;
      RECT 13.415 30.060 14.435 30.340 ;
      RECT 14.715 30.060 15.735 30.340 ;
      RECT 16.015 30.060 17.035 30.340 ;
      RECT 17.315 30.060 18.335 30.340 ;
      RECT 18.615 30.060 19.635 30.340 ;
      RECT 19.915 30.060 20.935 30.340 ;
      RECT 21.215 30.060 22.235 30.340 ;
      RECT 22.515 30.060 23.535 30.340 ;
      RECT 15.840 26.170 16.660 26.430 ;
      RECT 16.840 26.170 17.660 26.430 ;
      RECT 17.840 26.170 18.660 26.430 ;
      RECT 13.840 24.670 14.660 24.930 ;
      RECT 14.840 24.670 15.660 24.930 ;
      RECT 15.840 24.670 16.660 24.930 ;
      RECT 16.840 24.670 17.660 24.930 ;
      RECT 17.840 24.670 18.660 24.930 ;
      RECT 18.840 24.670 19.660 24.930 ;
      RECT 19.840 24.670 20.660 24.930 ;
      RECT 20.840 24.670 21.660 24.930 ;
      RECT 21.840 24.670 22.660 24.930 ;
      RECT 22.840 24.670 23.660 24.930 ;
      RECT 18.840 26.170 19.660 26.430 ;
      RECT 19.840 26.170 20.660 26.430 ;
      RECT 20.840 26.170 21.660 26.430 ;
      RECT 21.840 26.170 22.660 26.430 ;
      RECT 22.840 26.170 23.660 26.430 ;
      RECT 13.415 30.710 14.435 30.990 ;
      RECT 14.715 30.710 15.735 30.990 ;
      RECT 16.015 30.710 17.035 30.990 ;
      RECT 17.315 30.710 18.335 30.990 ;
      RECT 18.615 30.710 19.635 30.990 ;
      RECT 19.915 30.710 20.935 30.990 ;
      RECT 13.840 25.170 14.660 25.430 ;
      RECT 14.840 25.170 15.660 25.430 ;
      RECT 15.840 25.170 16.660 25.430 ;
      RECT 16.840 25.170 17.660 25.430 ;
      RECT 17.840 25.170 18.660 25.430 ;
      RECT 26.415 31.360 27.435 31.640 ;
      RECT 27.715 31.360 28.735 31.640 ;
      RECT 29.015 31.360 30.035 31.640 ;
      RECT 30.315 31.360 31.335 31.640 ;
      RECT 31.615 31.360 32.635 31.640 ;
      RECT 32.915 31.360 33.935 31.640 ;
      RECT 34.215 31.360 35.235 31.640 ;
      RECT 35.515 31.360 36.535 31.640 ;
      RECT 28.870 24.640 29.130 25.460 ;
      RECT 35.215 16.315 35.585 16.685 ;
      RECT 25.115 30.060 26.135 30.340 ;
      RECT 26.415 30.060 27.435 30.340 ;
      RECT 27.715 30.060 28.735 30.340 ;
      RECT 29.015 30.060 30.035 30.340 ;
      RECT 30.315 30.060 31.335 30.340 ;
      RECT 31.615 30.060 32.635 30.340 ;
      RECT 32.915 30.060 33.935 30.340 ;
      RECT 34.215 30.060 35.235 30.340 ;
      RECT 35.515 30.060 36.535 30.340 ;
      RECT 37.815 9.465 38.185 9.835 ;
      RECT 37.815 19.865 38.185 20.235 ;
      RECT 37.815 14.515 38.185 14.885 ;
      RECT 24.840 24.670 25.660 24.930 ;
      RECT 24.840 25.670 25.660 25.930 ;
      RECT 37.815 69.915 38.185 70.285 ;
      RECT 25.840 25.670 26.660 25.930 ;
      RECT 26.840 25.670 27.660 25.930 ;
      RECT 29.215 72.415 29.585 72.785 ;
      RECT 33.375 72.415 33.745 72.785 ;
      RECT 27.840 25.670 28.660 25.930 ;
      RECT 25.115 29.410 26.135 29.690 ;
      RECT 26.415 29.410 27.435 29.690 ;
      RECT 27.715 29.410 28.735 29.690 ;
      RECT 29.015 29.410 30.035 29.690 ;
      RECT 30.315 29.410 31.335 29.690 ;
      RECT 31.615 29.410 32.635 29.690 ;
      RECT 32.915 29.410 33.935 29.690 ;
      RECT 34.215 29.410 35.235 29.690 ;
      RECT 25.115 30.710 26.135 30.990 ;
      RECT 26.415 30.710 27.435 30.990 ;
      RECT 27.715 30.710 28.735 30.990 ;
      RECT 29.015 30.710 30.035 30.990 ;
      RECT 30.315 30.710 31.335 30.990 ;
      RECT 31.615 30.710 32.635 30.990 ;
      RECT 32.915 30.710 33.935 30.990 ;
      RECT 34.215 30.710 35.235 30.990 ;
      RECT 35.515 30.710 36.535 30.990 ;
      RECT 35.515 29.410 36.535 29.690 ;
      RECT 37.815 29.365 38.185 29.735 ;
      RECT 25.840 24.670 26.660 24.930 ;
      RECT 26.840 24.670 27.660 24.930 ;
      RECT 24.840 26.170 25.660 26.430 ;
      RECT 25.840 26.170 26.660 26.430 ;
      RECT 26.840 26.170 27.660 26.430 ;
      RECT 27.840 26.170 28.660 26.430 ;
      RECT 28.870 25.640 29.130 26.460 ;
      RECT 27.840 24.670 28.660 24.930 ;
      RECT 37.815 4.415 38.185 4.785 ;
      RECT 37.815 24.615 38.185 24.985 ;
      RECT 24.840 25.170 25.660 25.430 ;
      RECT 25.840 25.170 26.660 25.430 ;
      RECT 26.840 25.170 27.660 25.430 ;
      RECT 27.840 25.170 28.660 25.430 ;
      RECT 25.115 31.360 26.135 31.640 ;
    LAYER met3 ;
      RECT 23.185 29.385 24.165 29.715 ;
      RECT 23.185 30.035 24.165 30.365 ;
      RECT 23.185 30.685 24.165 31.015 ;
      RECT 23.185 31.335 24.165 31.665 ;
      RECT 5.950 35.385 8.500 35.885 ;
      RECT 9.500 35.385 43.900 35.885 ;
      RECT 8.500 35.135 9.500 36.135 ;
      RECT 5.950 43.785 8.500 44.285 ;
      RECT 9.500 43.785 43.900 44.285 ;
      RECT 8.500 43.535 9.500 44.535 ;
      RECT 5.950 52.185 8.500 52.685 ;
      RECT 9.500 52.185 43.900 52.685 ;
      RECT 8.500 51.935 9.500 52.935 ;
      RECT 5.950 60.585 8.500 61.085 ;
      RECT 9.500 60.585 43.900 61.085 ;
      RECT 8.500 60.335 9.500 61.335 ;
      RECT 37.750 69.850 39.000 70.350 ;
      RECT 40.000 69.850 43.900 70.350 ;
      RECT 39.000 69.600 40.000 70.600 ;
      RECT 6.990 72.350 7.490 72.850 ;
      RECT 7.040 69.850 7.440 72.350 ;
      RECT 1.300 69.850 7.040 70.350 ;
      RECT 29.150 72.350 29.650 72.850 ;
      RECT 29.200 68.850 29.600 72.350 ;
      RECT 1.300 68.850 29.200 69.350 ;
      RECT 33.310 72.350 33.810 72.850 ;
      RECT 33.360 67.850 33.760 72.350 ;
      RECT 1.300 67.850 33.360 68.350 ;
      RECT 29.150 80.250 29.650 80.750 ;
      RECT 29.200 76.750 29.600 80.250 ;
      RECT 1.300 76.750 29.200 77.250 ;
      RECT 33.310 80.250 33.810 80.750 ;
      RECT 33.360 75.750 33.760 80.250 ;
      RECT 1.300 75.750 33.360 76.250 ;
      RECT 29.150 88.405 29.650 88.905 ;
      RECT 29.200 84.905 29.600 88.405 ;
      RECT 1.300 84.905 29.200 85.405 ;
      RECT 33.310 88.405 33.810 88.905 ;
      RECT 33.360 83.905 33.760 88.405 ;
      RECT 1.300 83.905 33.360 84.405 ;
      RECT 29.150 96.305 29.650 96.805 ;
      RECT 29.200 92.805 29.600 96.305 ;
      RECT 1.300 92.805 29.200 93.305 ;
      RECT 33.310 96.305 33.810 96.805 ;
      RECT 33.360 91.805 33.760 96.305 ;
      RECT 1.300 91.805 33.360 92.305 ;
      RECT 25.000 104.460 25.500 104.960 ;
      RECT 25.050 100.960 25.450 104.460 ;
      RECT 1.300 100.960 25.050 101.460 ;
      RECT 27.500 104.460 28.000 104.960 ;
      RECT 27.550 99.960 27.950 104.460 ;
      RECT 1.300 99.960 27.550 100.460 ;
      RECT 25.000 112.335 25.500 112.835 ;
      RECT 25.050 108.835 25.450 112.335 ;
      RECT 1.300 108.835 25.050 109.335 ;
      RECT 27.500 112.335 28.000 112.835 ;
      RECT 27.550 107.835 27.950 112.335 ;
      RECT 1.300 107.835 27.550 108.335 ;
      RECT 27.750 120.485 28.250 120.985 ;
      RECT 27.800 116.985 28.200 120.485 ;
      RECT 1.300 116.985 27.800 117.485 ;
      RECT 30.550 120.485 31.050 120.985 ;
      RECT 30.600 115.985 31.000 120.485 ;
      RECT 1.300 115.985 30.600 116.485 ;
      RECT 27.750 135.535 28.250 136.035 ;
      RECT 27.800 132.035 28.200 135.535 ;
      RECT 1.300 132.035 27.800 132.535 ;
      RECT 30.550 135.535 31.050 136.035 ;
      RECT 30.600 131.035 31.000 135.535 ;
      RECT 1.300 131.035 30.600 131.535 ;
      RECT 37.750 101.960 39.000 102.460 ;
      RECT 40.000 101.960 43.900 102.460 ;
      RECT 39.000 101.710 40.000 102.710 ;
      RECT 29.050 112.335 39.000 112.835 ;
      RECT 40.000 112.335 45.900 112.835 ;
      RECT 39.000 112.085 40.000 113.085 ;
      RECT 37.750 117.985 39.000 118.485 ;
      RECT 40.000 117.985 43.900 118.485 ;
      RECT 39.000 117.735 40.000 118.735 ;
      RECT 37.750 93.805 39.000 94.305 ;
      RECT 40.000 93.805 43.900 94.305 ;
      RECT 39.000 93.555 40.000 94.555 ;
      RECT 37.750 77.750 39.000 78.250 ;
      RECT 40.000 77.750 43.900 78.250 ;
      RECT 39.000 77.500 40.000 78.500 ;
      RECT 37.750 133.035 39.000 133.535 ;
      RECT 40.000 133.035 43.900 133.535 ;
      RECT 39.000 132.785 40.000 133.785 ;
      RECT 37.750 109.835 39.000 110.335 ;
      RECT 40.000 109.835 43.900 110.335 ;
      RECT 39.000 109.585 40.000 110.585 ;
      RECT 37.750 85.905 39.000 86.405 ;
      RECT 40.000 85.905 43.900 86.405 ;
      RECT 39.000 85.655 40.000 86.655 ;
      RECT 2.000 112.335 2.500 112.835 ;
      RECT 2.050 111.335 2.450 112.335 ;
      RECT 1.300 110.835 2.450 111.335 ;
      RECT 4.500 112.335 5.000 112.835 ;
      RECT 4.550 109.835 4.950 112.335 ;
      RECT 1.300 109.835 4.550 110.335 ;
      RECT 6.990 96.305 7.490 96.805 ;
      RECT 7.040 93.805 7.440 96.305 ;
      RECT 1.300 93.805 7.040 94.305 ;
      RECT 2.830 88.405 3.330 88.905 ;
      RECT 2.880 86.905 3.280 88.405 ;
      RECT 1.300 86.905 2.880 87.405 ;
      RECT 6.990 88.405 7.490 88.905 ;
      RECT 7.040 85.905 7.440 88.405 ;
      RECT 1.300 85.905 7.040 86.405 ;
      RECT 2.830 72.350 3.330 72.850 ;
      RECT 2.880 70.850 3.280 72.350 ;
      RECT 1.300 70.850 2.880 71.350 ;
      RECT 2.150 120.485 2.650 120.985 ;
      RECT 2.200 119.485 2.600 120.485 ;
      RECT 1.300 118.985 2.600 119.485 ;
      RECT 4.950 120.485 5.450 120.985 ;
      RECT 5.000 117.985 5.400 120.485 ;
      RECT 1.300 117.985 5.000 118.485 ;
      RECT 2.000 104.460 2.500 104.960 ;
      RECT 2.050 103.460 2.450 104.460 ;
      RECT 1.300 102.960 2.450 103.460 ;
      RECT 4.500 104.460 5.000 104.960 ;
      RECT 4.550 101.960 4.950 104.460 ;
      RECT 1.300 101.960 4.550 102.460 ;
      RECT 2.830 80.250 3.330 80.750 ;
      RECT 2.880 78.750 3.280 80.250 ;
      RECT 1.300 78.750 2.880 79.250 ;
      RECT 2.150 135.535 2.650 136.035 ;
      RECT 2.200 134.535 2.600 135.535 ;
      RECT 1.300 134.035 2.600 134.535 ;
      RECT 4.950 135.535 5.450 136.035 ;
      RECT 5.000 133.035 5.400 135.535 ;
      RECT 1.300 133.035 5.000 133.535 ;
      RECT 6.990 80.250 7.490 80.750 ;
      RECT 7.040 77.750 7.440 80.250 ;
      RECT 1.300 77.750 7.040 78.250 ;
      RECT 2.830 96.305 3.330 96.805 ;
      RECT 2.880 94.805 3.280 96.305 ;
      RECT 1.300 94.805 2.880 95.305 ;
      RECT 14.085 30.685 15.065 31.015 ;
      RECT 15.385 30.685 16.365 31.015 ;
      RECT 16.685 30.685 17.665 31.015 ;
      RECT 17.985 30.685 18.965 31.015 ;
      RECT 19.285 30.685 20.265 31.015 ;
      RECT 20.585 30.685 21.565 31.015 ;
      RECT 21.885 30.685 22.865 31.015 ;
      RECT 1.300 9.400 3.750 9.900 ;
      RECT 4.985 31.335 5.965 31.665 ;
      RECT 6.285 31.335 7.265 31.665 ;
      RECT 7.585 31.335 8.565 31.665 ;
      RECT 8.885 31.335 9.865 31.665 ;
      RECT 10.185 31.335 11.165 31.665 ;
      RECT 11.485 31.335 12.465 31.665 ;
      RECT 12.785 31.335 13.765 31.665 ;
      RECT 14.085 31.335 15.065 31.665 ;
      RECT 15.385 31.335 16.365 31.665 ;
      RECT 16.685 31.335 17.665 31.665 ;
      RECT 17.985 31.335 18.965 31.665 ;
      RECT 19.285 31.335 20.265 31.665 ;
      RECT 20.585 31.335 21.565 31.665 ;
      RECT 21.885 31.335 22.865 31.665 ;
      RECT 1.300 11.200 3.750 11.700 ;
      RECT 3.750 31.335 4.665 31.665 ;
      RECT 1.300 31.250 3.750 31.750 ;
      RECT 1.300 34.250 7.755 34.750 ;
      RECT 1.300 14.450 3.750 14.950 ;
      RECT 1.300 36.440 3.700 36.940 ;
      RECT 1.300 39.650 5.940 40.150 ;
      RECT 1.300 42.650 7.755 43.150 ;
      RECT 1.300 16.250 3.750 16.750 ;
      RECT 1.300 44.840 3.700 45.340 ;
      RECT 1.300 48.050 5.940 48.550 ;
      RECT 1.300 51.050 7.755 51.550 ;
      RECT 1.300 19.800 3.750 20.300 ;
      RECT 1.300 53.240 3.700 53.740 ;
      RECT 1.300 56.450 5.940 56.950 ;
      RECT 1.300 59.450 7.755 59.950 ;
      RECT 1.300 21.300 3.750 21.800 ;
      RECT 1.300 61.640 3.700 62.140 ;
      RECT 1.300 64.850 5.940 65.350 ;
      RECT 1.300 24.550 3.750 25.050 ;
      RECT 1.300 26.050 3.750 26.550 ;
      RECT 4.985 29.385 5.965 29.715 ;
      RECT 6.285 29.385 7.265 29.715 ;
      RECT 7.585 29.385 8.565 29.715 ;
      RECT 8.885 29.385 9.865 29.715 ;
      RECT 10.185 29.385 11.165 29.715 ;
      RECT 11.485 29.385 12.465 29.715 ;
      RECT 12.785 29.385 13.765 29.715 ;
      RECT 14.085 29.385 15.065 29.715 ;
      RECT 15.385 29.385 16.365 29.715 ;
      RECT 16.685 29.385 17.665 29.715 ;
      RECT 17.985 29.385 18.965 29.715 ;
      RECT 19.285 29.385 20.265 29.715 ;
      RECT 20.585 29.385 21.565 29.715 ;
      RECT 21.885 29.385 22.865 29.715 ;
      RECT 1.300 4.350 3.750 4.850 ;
      RECT 3.750 29.385 4.665 29.715 ;
      RECT 1.300 29.300 3.750 29.800 ;
      RECT 4.985 30.035 5.965 30.365 ;
      RECT 6.285 30.035 7.265 30.365 ;
      RECT 7.585 30.035 8.565 30.365 ;
      RECT 8.885 30.035 9.865 30.365 ;
      RECT 10.185 30.035 11.165 30.365 ;
      RECT 11.485 30.035 12.465 30.365 ;
      RECT 12.785 30.035 13.765 30.365 ;
      RECT 14.085 30.035 15.065 30.365 ;
      RECT 15.385 30.035 16.365 30.365 ;
      RECT 16.685 30.035 17.665 30.365 ;
      RECT 17.985 30.035 18.965 30.365 ;
      RECT 19.285 30.035 20.265 30.365 ;
      RECT 20.585 30.035 21.565 30.365 ;
      RECT 21.885 30.035 22.865 30.365 ;
      RECT 1.300 6.150 3.750 6.650 ;
      RECT 4.335 30.035 4.665 31.015 ;
      RECT 4.985 30.685 5.965 31.015 ;
      RECT 6.285 30.685 7.265 31.015 ;
      RECT 7.585 30.685 8.565 31.015 ;
      RECT 8.885 30.685 9.865 31.015 ;
      RECT 10.185 30.685 11.165 31.015 ;
      RECT 11.485 30.685 12.465 31.015 ;
      RECT 12.785 30.685 13.765 31.015 ;
      RECT 27.085 30.685 28.065 31.015 ;
      RECT 28.385 30.685 29.365 31.015 ;
      RECT 29.685 30.685 30.665 31.015 ;
      RECT 30.985 30.685 31.965 31.015 ;
      RECT 32.285 30.685 33.265 31.015 ;
      RECT 33.585 30.685 34.565 31.015 ;
      RECT 34.885 30.685 35.865 31.015 ;
      RECT 24.485 30.035 25.465 30.365 ;
      RECT 25.785 30.035 26.765 30.365 ;
      RECT 27.085 30.035 28.065 30.365 ;
      RECT 28.385 30.035 29.365 30.365 ;
      RECT 29.685 30.035 30.665 30.365 ;
      RECT 30.985 30.035 31.965 30.365 ;
      RECT 32.285 30.035 33.265 30.365 ;
      RECT 33.585 30.035 34.565 30.365 ;
      RECT 34.885 30.035 35.865 30.365 ;
      RECT 36.185 29.385 36.515 30.365 ;
      RECT 37.750 29.300 39.000 29.800 ;
      RECT 40.000 29.300 43.900 29.800 ;
      RECT 39.000 29.050 40.000 30.050 ;
      RECT 37.750 24.550 39.000 25.050 ;
      RECT 40.000 24.550 43.900 25.050 ;
      RECT 39.000 24.300 40.000 25.300 ;
      RECT 35.150 16.250 39.000 16.750 ;
      RECT 40.000 16.250 45.900 16.750 ;
      RECT 39.000 16.000 40.000 17.000 ;
      RECT 37.750 9.400 39.000 9.900 ;
      RECT 40.000 9.400 43.900 9.900 ;
      RECT 39.000 9.150 40.000 10.150 ;
      RECT 37.750 19.800 39.000 20.300 ;
      RECT 40.000 19.800 43.900 20.300 ;
      RECT 39.000 19.550 40.000 20.550 ;
      RECT 24.485 31.335 25.465 31.665 ;
      RECT 25.785 31.335 26.765 31.665 ;
      RECT 27.085 31.335 28.065 31.665 ;
      RECT 28.385 31.335 29.365 31.665 ;
      RECT 29.685 31.335 30.665 31.665 ;
      RECT 30.985 31.335 31.965 31.665 ;
      RECT 32.285 31.335 33.265 31.665 ;
      RECT 33.585 31.335 34.565 31.665 ;
      RECT 34.885 31.335 35.865 31.665 ;
      RECT 36.185 30.685 36.515 31.665 ;
      RECT 37.750 14.450 39.000 14.950 ;
      RECT 40.000 14.450 43.900 14.950 ;
      RECT 39.000 14.200 40.000 15.200 ;
      RECT 24.485 29.385 25.465 29.715 ;
      RECT 25.785 29.385 26.765 29.715 ;
      RECT 27.085 29.385 28.065 29.715 ;
      RECT 28.385 29.385 29.365 29.715 ;
      RECT 29.685 29.385 30.665 29.715 ;
      RECT 30.985 29.385 31.965 29.715 ;
      RECT 32.285 29.385 33.265 29.715 ;
      RECT 33.585 29.385 34.565 29.715 ;
      RECT 34.885 29.385 35.865 29.715 ;
      RECT 37.750 4.350 39.000 4.850 ;
      RECT 40.000 4.350 43.900 4.850 ;
      RECT 39.000 4.100 40.000 5.100 ;
      RECT 24.485 30.685 25.465 31.015 ;
      RECT 25.785 30.685 26.765 31.015 ;
  END
END tp_bandl

END LIBRARY
